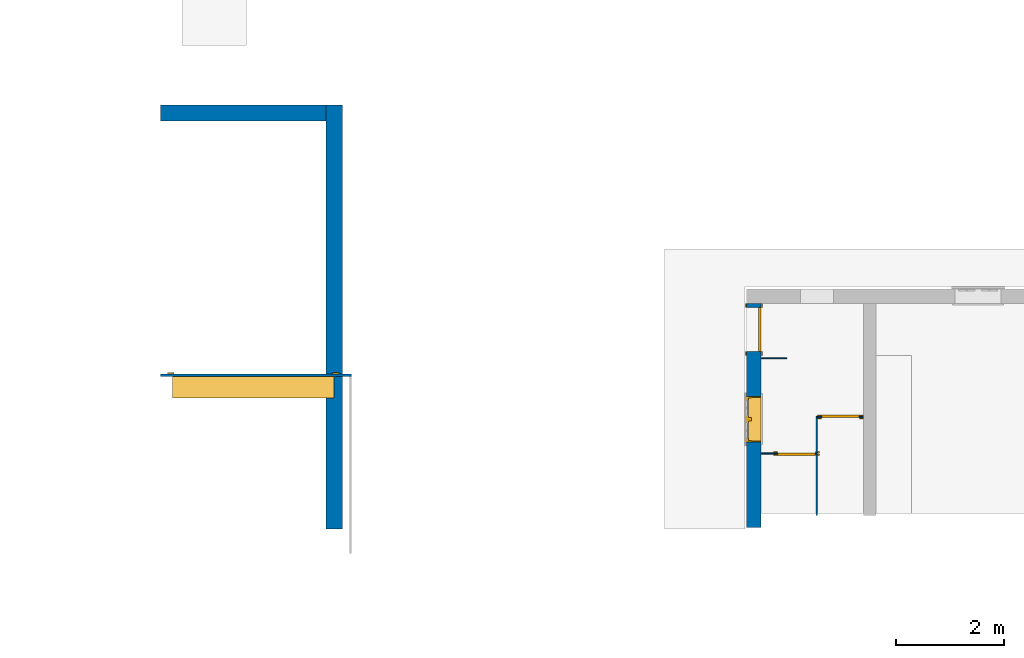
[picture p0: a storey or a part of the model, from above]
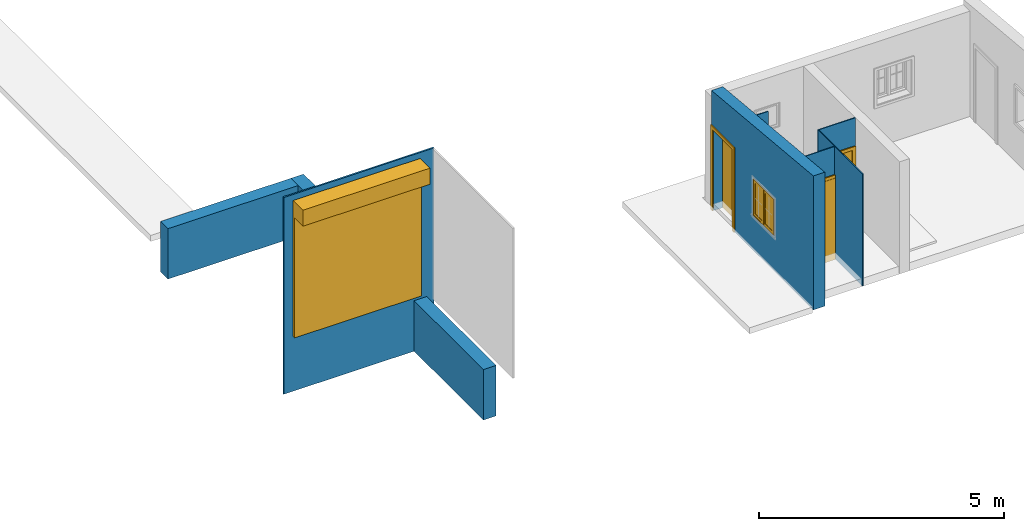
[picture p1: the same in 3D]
Properties of the parts of a building model (IFC2X3)

# File
Description: ViewDefinition [CoordinationView_V2.0]
File name: 1439
Time: 2020-03-18T17:45:13
Written by: The EXPRESS Data Manager Version 5.02.0100.07 : 28 Aug 2013
Made in: 20181011_1500(x64) - Exporter 18.3.2.7 - Alternate UI 18.3.2.7
Comment: STEP Physical File produced by: The EXPRESS Data Manager Version 5.02.0100.07 : 28 Aug 2013 * Module: EDMstepFileFactory/EDMstandAlone * Creation date: Wed Mar 18 17:45:13 2020 * Host: USER-PC * Database: C:\Users\xolad\AppData\Local\Temp\{D7F0864C-7578-4FBB-A1C1-AD8B3B978229}\ifc * Database version: 5507 * Database creation date: Wed Mar 18 17:45:00 2020 * Schema: IFC2X3 * Model: DataRepository.ifc * Model creation date: Wed Mar 18 17:45:00 2020 * Header model: DataRepository.ifc_HeaderModel * Header model creation date: Wed Mar 18 17:45:00 2020 * EDMuser: sdai-user * EDMgroup: sdai-group * License ID and type: 5605 : Permanent license. Expiry date: * EDMstepFileFactory options: 020000

# IfcProject, 1439
LongName: Sundale expansion; Phase: Concept

# IfcSite, Surface:366804
RefLatitude: 42, 24, 53, 508911; RefLongitude: -71, -15, -29, -58837; RefElevation: -44170 mm

# IfcBuilding
Pset_BuildingCommon - NumberOfStoreys: 7

# IfcBuildingStorey (7)
Name | LongName | Elevation (mm)
0. Base level | 0. Base level | 0
Hardstand | Hardstand | 42810
Ground FFL | Ground FFL | 44170
Ceiling 3500 | Ceiling 3500 | 47670
First floor | First floor | 48170
Ceiling 6000 | Ceiling 6000 | 50170
2nd floor | 2nd floor | 51027.1

# IfcBuildingElementProxy: Fascia:Fascia (2)
In: Ground FFL
Pset_BuildingElementProxyCommon - Reference: Fascia
Name (Fascia:...)
Fascia | Group: Model Group:Group 6:617275
Fascia

# IfcBuildingElementProxy: Generic Models 1, Generic Models 17:Generic Models 1:362068
In: Ground FFL
Pset_BuildingElementProxyCommon - Reference: Generic Models 1

# IfcBuildingElementProxy: Generic Models 12 (2)
In: 2nd floor
Pset_BuildingElementProxyCommon - Reference: Generic Models 12
Name
Generic Models 27:Generic Models 12:363948
Generic Models 28:Generic Models 12:363960

# IfcBuildingElementProxy: Generic Models 16, Generic Models 16:Generic Models 16:437957
In: First floor
Type - Material: Column
Pset_BuildingElementProxyCommon - Reference: Generic Models 16

# IfcBuildingElementProxy: Generic Models 2 (2)
In: 2nd floor
Type - Material: Orange
Pset_BuildingElementProxyCommon - Reference: Generic Models 2
Name
Generic Models 18:Generic Models 2:362203
Generic Models 19:Generic Models 2:362217

# IfcBuildingElementProxy: Generic Models 23 (2)
Type - Material: Aluminum, Anodized Silver
Pset_BuildingElementProxyCommon - Reference: Generic Models 23
Name | In
Generic Models 23:Generic Models 23:452494 | Ceiling 3500
Generic Models 26:Generic Models 23:457799 | Ceiling 6000

# IfcBuildingElementProxy: Generic Models 24, Generic Models 24:Generic Models 24:468942
In: First floor
Pset_BuildingElementProxyCommon - Reference: Generic Models 24

# IfcBuildingElementProxy: Generic Models 30, Generic Models 30:Generic Models 30:745945
In: Hardstand
Type - Material: Aluminum, Anodized Silver
Pset_BuildingElementProxyCommon - Reference: Generic Models 30

# IfcBuildingElementProxy: Generic Models 32, Generic Models 64:Generic Models 32:691842
In: Ground FFL
Type - Material: Parking Stripe
Pset_BuildingElementProxyCommon - Reference: Generic Models 32
Group: Model Group:Group 8:726659

# IfcBuildingElementProxy: Generic Models 32 (10)
In: Ground FFL
Type - Material: conc bund
Pset_BuildingElementProxyCommon - Reference: Generic Models 32
Group: Model Group:Group 8:726659
Name
Generic Models 32:Generic Models 32:688641
Generic Models 34:Generic Models 32:688682
Generic Models 61:Generic Models 32:688970
Generic Models 65:Generic Models 32:689397
Generic Models 66:Generic Models 32:689933
Generic Models 38:Generic Models 32:690142
Generic Models 62:Generic Models 32:690381
Generic Models 40:Generic Models 32:691201
Generic Models 67:Generic Models 32:726229
Generic Models 63:Generic Models 32:770716

# IfcBuildingElementProxy: Generic Models 4, Generic Models 20:Generic Models 4:362298
In: Hardstand
Type - Material: Copper
Pset_BuildingElementProxyCommon - Reference: Generic Models 4

# IfcBuildingElementProxy: Generic Models 43, Generic Models 43:Generic Models 43:692555
In: 2nd floor
Type - Material: Aluminum, Anodized Silver
Pset_BuildingElementProxyCommon - Reference: Generic Models 43

# IfcBuildingElementProxy: Generic Models 44 (17)
Type - Material: bollards
Pset_BuildingElementProxyCommon - Reference: Generic Models 44
Name | In | Group
Generic Models 44:Generic Models 44:753895 | 0. Base level
Generic Models 45:Generic Models 44:754462 | 0. Base level | Model Group:Array Group 3:754972
Generic Models 46:Generic Models 44:754982 | 0. Base level | Model Group:Array Group 3:754991
Generic Models 47:Generic Models 44:755017 | 0. Base level | Model Group:Array Group 3:755026
Generic Models 48:Generic Models 44:755035 | 0. Base level | Model Group:Array Group 3:755044
Generic Models 49:Generic Models 44:755053 | 0. Base level | Model Group:Array Group 3:755062
Generic Models 50:Generic Models 44:755071 | 0. Base level | Model Group:Array Group 3:755080
Generic Models 51:Generic Models 44:755089 | 0. Base level | Model Group:Array Group 3:755098
Generic Models 52:Generic Models 44:755107 | 0. Base level | Model Group:Array Group 3:755116
Generic Models 53:Generic Models 44:755125 | 0. Base level | Model Group:Array Group 3:755134
Generic Models 54:Generic Models 44:755143 | 0. Base level | Model Group:Array Group 3:755152
Generic Models 55:Generic Models 44:755161 | 0. Base level | Model Group:Array Group 3:755170
Generic Models 56:Generic Models 44:755179 | 0. Base level | Model Group:Array Group 3:755188
Generic Models 57:Generic Models 44:755197 | 0. Base level | Model Group:Array Group 3:755206
Generic Models 58:Generic Models 44:755215 | 0. Base level | Model Group:Array Group 3:755224
Generic Models 59:Generic Models 44:757700 | 0. Base level
Generic Models 60:Generic Models 44:758977 | Hardstand

# IfcBuildingElementProxy: Generic Models 5 (3)
In: First floor
Type - Material: Column
Pset_BuildingElementProxyCommon - Reference: Generic Models 5
Name
Generic Models 22:Generic Models 5:363155
Generic Models 9:Generic Models 5:470025
Generic Models 29:Generic Models 5:485776

# IfcBuildingElementProxy: Generic Models 68, Generic Models 68:Generic Models 68:786691
In: Ceiling 3500
Type - Material: fence
Pset_BuildingElementProxyCommon - Reference: Generic Models 68

# IfcBuildingElementProxy: Generic Models 7 (3)
Type - Material: Column
Pset_BuildingElementProxyCommon - Reference: Generic Models 7
Name | In
Generic Models 21:Generic Models 7:362919 | 0. Base level
Generic Models 7:Generic Models 7:430327 | Ground FFL
Generic Models 15:Generic Models 7:435619 | Ground FFL

# IfcBuildingElementProxy: Japanese Maple - 3.0 Meters (3)
In: Hardstand
Pset_BuildingElementProxyCommon - Reference: Japanese Maple - 3.0 Meters
Name (M_RPC Tree - Deciduous:Japanese Maple - 3.0 Meters:...)
405666
405705
405730

# IfcBuildingElementProxy: Largetooth Aspen - 7.6 Meters (2)
Pset_BuildingElementProxyCommon - Reference: Largetooth Aspen - 7.6 Meters
Name (M_RPC Tree - Deciduous:Largetooth Aspen - 7.6 Meters:...) | In
465073 | 0. Base level
465143 | Hardstand

# IfcBuildingElementProxy: Lombardy Poplar - 12.2 Meters (2)
In: Hardstand
Pset_BuildingElementProxyCommon - Reference: Lombardy Poplar - 12.2 Meters
Name (M_RPC Tree - Deciduous:Lombardy Poplar - 12.2 Meters:...)
465183
465230

# IfcBuildingElementProxy: M_Muntin Pattern_2x2 (6)
In: Hardstand
Type - Material: Clad - White, Wood - Stained
Pset_BuildingElementProxyCommon - Reference: M_Muntin Pattern_2x2
Group: Model Group:Group 6:617275
Name (M_Muntin Pattern_2x2:M_Muntin Pattern_2x2:...)
534044
534045
536291
536292
536326
536327

# IfcBuildingElementProxy: Picture Frame (3)
In: Hardstand
Type - Material: Wood - Stained
Pset_BuildingElementProxyCommon - Reference: Picture Frame
Group: Model Group:Group 6:617275
Name (M_Trim-Window-Interior-Flat:Picture Frame:...)
534047
536294
536329

# IfcBuildingElementProxy: Truck03 (3)
Pset_BuildingElementProxyCommon - Reference: Truck03
Name (Truck03:Truck03:...) | In
362314 | Ground FFL
363380 | Hardstand
363381 | Hardstand

# IfcBuildingElementProxy: locker (7)
In: 2nd floor
Type - Material: Laminate, Ivory, Matte, Wood Sheathing, Chipboard
Pset_BuildingElementProxyCommon - Reference: locker
Name (locker:locker:...)
509001
510158
510176
510204
510205
510206
511701

# IfcBuildingElementProxy: lockers 2 (47)
In: First floor
Type - Material: Laminate, Ivory, Matte
Pset_BuildingElementProxyCommon - Reference: lockers 2
Name (lockers 2:lockers 2:...) | Group
636421 | Model Group:Array Group 1:636530
636635 | Model Group:Array Group 1:636636
636703 | Model Group:Array Group 1:636704
636735 | Model Group:Array Group 1:636736
636767 | Model Group:Array Group 1:636768
636799 | Model Group:Array Group 1:636800
636831 | Model Group:Array Group 1:636832
636863 | Model Group:Array Group 1:636864
636895 | Model Group:Array Group 1:636896
636927 | Model Group:Array Group 1:636928
636959 | Model Group:Array Group 1:636960
636991 | Model Group:Array Group 1:636992
637023 | Model Group:Array Group 1:637024
637055 | Model Group:Array Group 1:637056
637087 | Model Group:Array Group 1:637088
637119 | Model Group:Array Group 1:637120
637162 | Model Group:Array Group 1:637163
637194 | Model Group:Array Group 1:637195
637268 | Model Group:Array Group 1:637269
637300 | Model Group:Array Group 1:637301
637348 | Model Group:Array Group 1:637349
637380 | Model Group:Array Group 1:637381
637456 | Model Group:Array Group 1:637457
637488 | Model Group:Array Group 1:637489
637520 | Model Group:Array Group 1:637521
637552 | Model Group:Array Group 1:637553
637584 | Model Group:Array Group 1:637585
637616 | Model Group:Array Group 1:637617
637648 | Model Group:Array Group 1:637649
637680 | Model Group:Array Group 1:637681
637712 | Model Group:Array Group 1:637713
637755 | Model Group:Array Group 1:637756
637815 | Model Group:Array Group 1:637816
637874 | Model Group:Array Group 1:637875
637939 | Model Group:Array Group 1:637940
638002 | Model Group:Array Group 1:638003
638034 | Model Group:Array Group 1:638035
638066 | Model Group:Array Group 1:638067
638098 | Model Group:Array Group 1:638099
638142 | Model Group:Array Group 1:638143
638184 | Model Group:Array Group 1:638185
638186 | Model Group:Array Group 1:638187
638188 | Model Group:Array Group 1:638189
638190 | Model Group:Array Group 1:638191
638192 | Model Group:Array Group 1:638193
638194 | Model Group:Array Group 1:638195
638196 | Model Group:Array Group 1:638197

# IfcBuildingElementProxy: turnstile (2)
In: Ground FFL
Type - Material: metal
Pset_BuildingElementProxyCommon - Reference: turnstile
Name (turnstile:turnstile:...)
711251
712248

# IfcBuildingElementProxy: with Sill (3)
In: Hardstand
Type - Material: Clad - White
Pset_BuildingElementProxyCommon - Reference: with Sill
Group: Model Group:Group 6:617275
Name (M_Trim-Window-Exterior-Flat:with Sill:...)
534046
536293
536328

# IfcCurtainWall: Curtain Wall:Storefront (14)
Pset_CurtainWallCommon - IsExternal: yes; Reference: Storefront
Name (Curtain Wall:Storefront:...) | In
363622 | Ground FFL
452065 | Ground FFL
573182 | 2nd floor
590973 | Ground FFL
624712 | Ground FFL
624715 | Ground FFL
624717 | Ground FFL
624719 | Ground FFL
652019 | First floor
652436 | First floor
662282 | 2nd floor
662335 | 2nd floor
679730 | Ground FFL
679854 | Ground FFL

# IfcDoor: 0813 x 2030mm (4)
Type - OperationType: SINGLE_SWING_LEFT; ParameterTakesPrecedence: no; Sizeable: no; Material: Door - Frame, Door - Panel
Type - M_Single-Flush:0813 x 2030mm:511926 - PanelOperation: SWINGING
OverallHeight: 2030 mm; OverallWidth: 813 mm
Pset_DoorCommon - IsExternal: no; Reference: 0813 x 2030mm; ThermalTransmittance: 3.7021 kg/K/s3
Name (M_Single-Flush:0813 x 2030mm:...) | In
511926 | 2nd floor
524189 | First floor
525468 | First floor
580034 | First floor

# IfcDoor: 0813 x 2030mm, M_Single-Flush:0813 x 2030mm:520814
In: First floor
Type - OperationType: SINGLE_SWING_LEFT; ParameterTakesPrecedence: no; Sizeable: no; Material: Door - Frame, Door - Panel
Type - M_Single-Flush:0813 x 2030mm:520814 - PanelOperation: SWINGING
OverallHeight: 2030 mm; OverallWidth: 813 mm
Pset_DoorCommon - IsExternal: no; Reference: 0813 x 2030mm; ThermalTransmittance: 3.7021 kg/K/s3

# IfcDoor: 0813 x 2030mm (3)
In: First floor
Type - OperationType: SINGLE_SWING_LEFT; ParameterTakesPrecedence: no; Sizeable: no; Material: Door - Frame, Door - Panel
Type - M_Single-Flush:0813 x 2030mm:525263 - PanelOperation: SWINGING
OverallHeight: 2030 mm; OverallWidth: 813 mm
Pset_DoorCommon - IsExternal: no; Reference: 0813 x 2030mm; ThermalTransmittance: 3.7021 kg/K/s3
Name (M_Single-Flush:0813 x 2030mm:...)
525263
525330
579933

# IfcDoor: 0813 x 2030mm, M_Single-Flush:0813 x 2030mm:535025
In: Hardstand
Type - OperationType: SINGLE_SWING_LEFT; ParameterTakesPrecedence: no; Sizeable: no; Material: Door - Frame, Door - Panel
Type - M_Single-Flush:0813 x 2030mm:535025 - PanelOperation: SWINGING
OverallHeight: 2030 mm; OverallWidth: 813 mm; Group: Model Group:Group 6:617275
Pset_DoorCommon - IsExternal: no; Reference: 0813 x 2030mm; ThermalTransmittance: 3.7021 kg/K/s3

# IfcDoor: 0813 x 2030mm (4)
Type - OperationType: SINGLE_SWING_RIGHT; ParameterTakesPrecedence: no; Sizeable: no; Material: Door - Frame, Door - Panel
Type - M_Single-Flush:0813 x 2030mm:512172 - PanelOperation: SWINGING
OverallHeight: 2030 mm; OverallWidth: 813 mm
Pset_DoorCommon - IsExternal: no; Reference: 0813 x 2030mm; ThermalTransmittance: 3.7021 kg/K/s3
Name (M_Single-Flush:0813 x 2030mm:...) | In
512172 | 2nd floor
523256 | First floor
524791 | First floor
524841 | First floor

# IfcDoor: 0813 x 2030mm, M_Single-Flush:0813 x 2030mm:521029
In: 2nd floor
Type - OperationType: SINGLE_SWING_RIGHT; ParameterTakesPrecedence: no; Sizeable: no; Material: Door - Frame, Door - Panel
Type - M_Single-Flush:0813 x 2030mm:521029 - PanelOperation: SWINGING
OverallHeight: 2030 mm; OverallWidth: 813 mm
Pset_DoorCommon - IsExternal: no; Reference: 0813 x 2030mm; ThermalTransmittance: 3.7021 kg/K/s3

# IfcDoor: 0813 x 2030mm (2)
Type - OperationType: SINGLE_SWING_RIGHT; ParameterTakesPrecedence: no; Sizeable: no; Material: Door - Frame, Door - Panel
Type - M_Single-Flush:0813 x 2030mm:522150 - PanelOperation: SWINGING
OverallHeight: 2030 mm; OverallWidth: 813 mm
Pset_DoorCommon - IsExternal: no; Reference: 0813 x 2030mm; ThermalTransmittance: 3.7021 kg/K/s3
Name (M_Single-Flush:0813 x 2030mm:...) | In
522150 | 2nd floor
536511 | Ground FFL

# IfcDoor: 0813 x 2030mm (4)
In: First floor
Type - OperationType: SINGLE_SWING_RIGHT; ParameterTakesPrecedence: no; Sizeable: no; Material: Door - Frame, Door - Panel
Type - M_Single-Flush:0813 x 2030mm:527921 - PanelOperation: SWINGING
OverallHeight: 2030 mm; OverallWidth: 813 mm
Pset_DoorCommon - IsExternal: no; Reference: 0813 x 2030mm; ThermalTransmittance: 3.7021 kg/K/s3
Name (M_Single-Flush:0813 x 2030mm:...)
527921
528006
528034
528060

# IfcDoor: 0813 x 2030mm, M_Single-Flush:0813 x 2030mm:534794
In: Hardstand
Type - OperationType: SINGLE_SWING_RIGHT; ParameterTakesPrecedence: no; Sizeable: no; Material: Door - Frame, Door - Panel
Type - M_Single-Flush:0813 x 2030mm:534794 - PanelOperation: SWINGING
OverallHeight: 2030 mm; OverallWidth: 813 mm; Group: Model Group:Group 6:617275
Pset_DoorCommon - IsExternal: no; Reference: 0813 x 2030mm; ThermalTransmittance: 3.7021 kg/K/s3

# IfcDoor: 0813 x 2134mm, M_Single-Flush:0813 x 2134mm:640715
In: First floor
Type - OperationType: SINGLE_SWING_LEFT; ParameterTakesPrecedence: no; Sizeable: no; Material: Door - Frame, Door - Panel
Type - M_Single-Flush:0813 x 2134mm:640715 - PanelOperation: SWINGING
OverallHeight: 2134 mm; OverallWidth: 813 mm
Pset_DoorCommon - IsExternal: no; Reference: 0813 x 2134mm; ThermalTransmittance: 3.7021 kg/K/s3

# IfcDoor: 1050 x 2134mm (7)
In: Ground FFL
Type - OperationType: SINGLE_SWING_LEFT; ParameterTakesPrecedence: no; Sizeable: no; Material: Door - Frame, Door - Panel
Type - M_Single-Flush:1050 x 2134mm:525980 - PanelOperation: SWINGING
OverallHeight: 2134 mm; OverallWidth: 1050 mm
Pset_DoorCommon - IsExternal: no; Reference: 1050 x 2134mm; ThermalTransmittance: 3.7021 kg/K/s3
Name (M_Single-Flush:1050 x 2134mm:...)
525980
526156
526285
526328
526460
659010
782430

# IfcDoor: 1050 x 2134mm, M_Single-Flush:1050 x 2134mm:769808
In: First floor
Type - OperationType: SINGLE_SWING_LEFT; ParameterTakesPrecedence: no; Sizeable: no; Material: Door - Frame, Door - Panel
Type - M_Single-Flush:1050 x 2134mm:769808 - PanelOperation: SWINGING
OverallHeight: 2134 mm; OverallWidth: 1050 mm
Pset_DoorCommon - IsExternal: no; Reference: 1050 x 2134mm; ThermalTransmittance: 3.7021 kg/K/s3

# IfcDoor: 1050 x 2134mm (8)
In: Ground FFL
Type - OperationType: SINGLE_SWING_RIGHT; ParameterTakesPrecedence: no; Sizeable: no; Material: Door - Frame, Door - Panel
Type - M_Single-Flush:1050 x 2134mm:526187 - PanelOperation: SWINGING
OverallHeight: 2134 mm; OverallWidth: 1050 mm
Pset_DoorCommon - IsExternal: no; Reference: 1050 x 2134mm; ThermalTransmittance: 3.7021 kg/K/s3
Name (M_Single-Flush:1050 x 2134mm:...)
526187
526288
526434
659299
659471
660703
660745
678601

# IfcDoor: 1050 x 3000mm, M_Single-Flush:1050 x 3000mm:526374
In: Ground FFL
Type - OperationType: SINGLE_SWING_LEFT; ParameterTakesPrecedence: no; Sizeable: no; Material: Door - Frame, Door - Panel
Type - M_Single-Flush:1050 x 3000mm:526374 - PanelOperation: SWINGING
OverallHeight: 3000 mm; OverallWidth: 1050 mm
Pset_DoorCommon - IsExternal: no; Reference: 1050 x 3000mm; ThermalTransmittance: 3.7021 kg/K/s3

# IfcDoor: 1050 x 3000mm, M_Single-Flush:1050 x 3000mm:526406
In: Ground FFL
Type - OperationType: SINGLE_SWING_RIGHT; ParameterTakesPrecedence: no; Sizeable: no; Material: Door - Frame, Door - Panel
Type - M_Single-Flush:1050 x 3000mm:526406 - PanelOperation: SWINGING
OverallHeight: 3000 mm; OverallWidth: 1050 mm
Pset_DoorCommon - IsExternal: no; Reference: 1050 x 3000mm; ThermalTransmittance: 3.7021 kg/K/s3

# IfcDoor: 25000(w) x 3000(h) (6)
In: Ground FFL
Type - ParameterTakesPrecedence: no; Sizeable: no; Material: Metal - Paint Finish - Ivory, Matte, Metal - Galvanised
OverallHeight: 3000 mm; OverallWidth: 2500 mm
Pset_DoorCommon - IsExternal: yes; Reference: 25000(w) x 3000(h)
Name (Rollershutter:25000(w) x 3000(h):...)
363164
678529
678631
678650
781874
782168

# IfcDoor: 3000(w) x 3000(h) (3)
In: Ground FFL
Type - ParameterTakesPrecedence: no; Sizeable: no; Material: Metal - Paint Finish - Ivory, Matte, Metal - Galvanised
OverallHeight: 3000 mm; OverallWidth: 3000 mm
Pset_DoorCommon - IsExternal: yes; Reference: 3000(w) x 3000(h)
Name (Rollershutter:3000(w) x 3000(h):...)
440970
441001
681902

# IfcDoor: 3000(w) x 3000(h) (15)
In: Ground FFL
Type - ParameterTakesPrecedence: no; Sizeable: no; Material: Metal - Steel - Richards Wilcox - Painted - Brown - Ribbed, Metal - Steel - Richards Wilcox - Galvanized, Glazing - Richards Wilcox - Clear, Metal - Steel - Richards Wilcox - Painted - Black, Analytical Floor Surface, Rubber - Richards Wilcox - Black
OverallHeight: 3000 mm; OverallWidth: 2200 mm
Pset_DoorCommon - IsExternal: yes; Reference: 3000(w) x 3000(h)
Name (6m_Roller Shutter Doors:3000(w) x 3000(h):...)
399966
412640
412870
412898
412903
412908
412913
412918
412923
412928
412933
412938
412943
412948
412953

# IfcDoor: 700 x 2030mm (2)
In: 2nd floor
Type - OperationType: SINGLE_SWING_LEFT; ParameterTakesPrecedence: no; Sizeable: no; Material: Door - Frame, Door - Panel
Type - M_Single-Flush:700 x 2030mm:511005 - PanelOperation: SWINGING
OverallHeight: 2030 mm; OverallWidth: 700 mm
Pset_DoorCommon - IsExternal: no; Reference: 700 x 2030mm; ThermalTransmittance: 3.7021 kg/K/s3
Name (M_Single-Flush:700 x 2030mm:...)
511005
511007

# IfcDoor: 700 x 2030mm, M_Single-Flush:700 x 2030mm:572632
In: 2nd floor
Type - OperationType: SINGLE_SWING_LEFT; ParameterTakesPrecedence: no; Sizeable: no; Material: Door - Frame, Door - Panel
Type - M_Single-Flush:700 x 2030mm:572632 - PanelOperation: SWINGING
OverallHeight: 2030 mm; OverallWidth: 700 mm
Pset_DoorCommon - IsExternal: no; Reference: 700 x 2030mm; ThermalTransmittance: 3.7021 kg/K/s3

# IfcDoor: 700 x 2030mm (4)
Type - OperationType: SINGLE_SWING_RIGHT; ParameterTakesPrecedence: no; Sizeable: no; Material: Door - Frame, Door - Panel
Type - M_Single-Flush:700 x 2030mm:511009 - PanelOperation: SWINGING
OverallHeight: 2030 mm; OverallWidth: 700 mm
Pset_DoorCommon - IsExternal: no; Reference: 700 x 2030mm; ThermalTransmittance: 3.7021 kg/K/s3
Name (M_Single-Flush:700 x 2030mm:...) | In
511009 | 2nd floor
511010 | 2nd floor
533854 | Hardstand | Group: Model Group:Group 6:617275
533856 | Hardstand | Group: Model Group:Group 6:617275

# IfcDoor: 700 x 2030mm (2)
In: First floor
Type - OperationType: SINGLE_SWING_RIGHT; ParameterTakesPrecedence: no; Sizeable: no; Material: Door - Frame, Door - Panel
Type - M_Single-Flush:700 x 2030mm:524607 - PanelOperation: SWINGING
OverallHeight: 2030 mm; OverallWidth: 700 mm
Pset_DoorCommon - IsExternal: no; Reference: 700 x 2030mm; ThermalTransmittance: 3.7021 kg/K/s3
Name (M_Single-Flush:700 x 2030mm:...)
524607
524656

# IfcDoor: 700 x 2030mm, M_Single-Flush:700 x 2030mm:553800
In: Hardstand
Type - OperationType: SINGLE_SWING_RIGHT; ParameterTakesPrecedence: no; Sizeable: no; Material: Door - Frame, Door - Panel
Type - M_Single-Flush:700 x 2030mm:553800 - PanelOperation: SWINGING
OverallHeight: 2030 mm; OverallWidth: 700 mm
Pset_DoorCommon - IsExternal: no; Reference: 700 x 2030mm; ThermalTransmittance: 3.7021 kg/K/s3

# IfcDoor: 700 x 2030mm, M_Single-Flush:700 x 2030mm:588641
In: Hardstand
Type - OperationType: SINGLE_SWING_RIGHT; ParameterTakesPrecedence: no; Sizeable: no; Material: Door - Frame, Door - Panel
Type - M_Single-Flush:700 x 2030mm:588641 - PanelOperation: SWINGING
OverallHeight: 2030 mm; OverallWidth: 700 mm
Pset_DoorCommon - IsExternal: no; Reference: 700 x 2030mm; ThermalTransmittance: 3.7021 kg/K/s3

# IfcDoor: 813 x 2030mm (2)
In: First floor
Type - OperationType: SINGLE_SWING_LEFT; ParameterTakesPrecedence: no; Sizeable: no; Material: Door - Frame, Door - Panel
Type - M_Single-Flush:813 x 2030mm:406399 - PanelOperation: SWINGING
OverallHeight: 2030 mm; OverallWidth: 813 mm
Pset_DoorCommon - IsExternal: no; Reference: 813 x 2030mm; ThermalTransmittance: 3.7021 kg/K/s3
Name (M_Single-Flush:813 x 2030mm:...)
406399
621226

# IfcDoor: 813 x 2030mm, M_Single-Flush:813 x 2030mm:457723
In: Ground FFL
Type - OperationType: SINGLE_SWING_RIGHT; ParameterTakesPrecedence: no; Sizeable: no; Material: Door - Frame, Door - Panel
Type - M_Single-Flush:813 x 2030mm:457723 - PanelOperation: SWINGING
OverallHeight: 2030 mm; OverallWidth: 813 mm
Pset_DoorCommon - IsExternal: no; Reference: 813 x 2030mm; ThermalTransmittance: 3.7021 kg/K/s3

# IfcDoor: 813 x 2030mm (2)
In: First floor
Type - OperationType: SINGLE_SWING_RIGHT; ParameterTakesPrecedence: no; Sizeable: no; Material: Door - Frame, Door - Panel
Type - M_Single-Flush:813 x 2030mm:493220 - PanelOperation: SWINGING
OverallHeight: 2030 mm; OverallWidth: 813 mm
Pset_DoorCommon - IsExternal: no; Reference: 813 x 2030mm; ThermalTransmittance: 3.7021 kg/K/s3
Name (M_Single-Flush:813 x 2030mm:...)
493220
641769

# IfcDoor: 813 x 2030mm, M_Single-Flush:813 x 2030mm:784138
In: First floor
Type - OperationType: SINGLE_SWING_RIGHT; ParameterTakesPrecedence: no; Sizeable: no; Material: Door - Frame, Door - Panel
Type - M_Single-Flush:813 x 2030mm:784138 - PanelOperation: SWINGING
OverallHeight: 2030 mm; OverallWidth: 813 mm
Pset_DoorCommon - IsExternal: no; Reference: 813 x 2030mm; ThermalTransmittance: 3.7021 kg/K/s3

# IfcFlowTerminal: Concorde 510 (14)
Classification: D2010440 Sinks - Service (Uniformat)
Pset_ManufacturerTypeInformation - Manufacturer: VAAL
Pset_DistributionFlowElementCommon - Reference: Concorde 510
Name (duravit automatic tap no pedestal:Concorde 510:...) | In
501603 | 2nd floor
510610 | 2nd floor
510645 | 2nd floor
528683 | First floor
528718 | First floor
528761 | First floor
528808 | First floor
528867 | First floor
528896 | First floor
528927 | First floor
528954 | First floor
529224 | First floor
529317 | First floor
533354 | Ground FFL | Group: Model Group:Group 6:617275

# IfcFlowTerminal: Lavatera (8)
Classification: D2010210 Urinals - Single (Uniformat); Material: Porcelain - Linen
Pset_ManufacturerTypeInformation - Manufacturer: VAAL
Pset_DistributionFlowElementCommon - Reference: Lavatera
Name (Lavatera with Cobra Sensor:Lavatera:...) | In
511117 | 2nd floor
511118 | 2nd floor
511119 | 2nd floor
527367 | First floor
527396 | First floor
527447 | First floor
527478 | First floor
533690 | Ground FFL | Group: Model Group:Group 6:617275

# IfcFurnishingElement: Desk 900x1800 (7)
Type - ElementType: Desk 900x1800; Material: Paint - White
Name (Desk 900x1800:Desk 900x1800:...) | In
522024 | 2nd floor
522053 | 2nd floor
522074 | 2nd floor
522079 | 2nd floor
522100 | 2nd floor
522105 | 2nd floor
535153 | Ground FFL | Group: Model Group:Group 6:617275

# IfcFurnishingElement: Desk Chair (30)
Type - ElementType: Desk Chair; Material: Metal - Chrome, Textile - Slate Blue
Name (M_Chair-Desk:Desk Chair:...) | In
522025 | 2nd floor
522026 | 2nd floor
522027 | 2nd floor
522028 | 2nd floor
522054 | 2nd floor
522055 | 2nd floor
522056 | 2nd floor
522057 | 2nd floor
522075 | 2nd floor
522076 | 2nd floor
522077 | 2nd floor
522078 | 2nd floor
522080 | 2nd floor
522081 | 2nd floor
522082 | 2nd floor
522083 | 2nd floor
522101 | 2nd floor
522102 | 2nd floor
522103 | 2nd floor
522104 | 2nd floor
522106 | 2nd floor
522107 | 2nd floor
522108 | 2nd floor
522109 | 2nd floor
535154 | Ground FFL | Group: Model Group:Group 6:617275
535155 | Ground FFL | Group: Model Group:Group 6:617275
535156 | Ground FFL | Group: Model Group:Group 6:617275
535157 | Ground FFL | Group: Model Group:Group 6:617275
535215 | Ground FFL | Group: Model Group:Group 6:617275
535262 | Ground FFL | Group: Model Group:Group 6:617275

# IfcMember: Curtain Wall:Storefront:8486 (147)
Material: Aluminium
Pset_MemberCommon - IsExternal: yes; LoadBearing: yes; Reference: 50 x 150mm
Name (Curtain Wall:Storefront:...) | In | Span (mm)
4 x 8486 | Ground FFL | 875
3 x 8486 | Ground FFL | 920
6 x 8486 | Ground FFL | 1429.82
5 x 8486 | Ground FFL | 2220
5 x 8486 | Ground FFL | 580
6 x 8486 | Ground FFL | 1454.82
4 x 8486 | 2nd floor | 1425
4 x 8486 | 2nd floor | 966.879
2 x 8486 | 2nd floor | 1450
2 x 8486 | Ground FFL | 900
2 x 8486 | Ground FFL | 1000
12 x 8486 | Ground FFL | 991.667
20 x 8486 | Ground FFL | 2400
8 x 8486 | Ground FFL | 601.146
6 x 8486 | Ground FFL | 1016.67
12 x 8486 | Ground FFL | 941.667
6 x 8486 | Ground FFL | 966.667
14 x 8486 | Ground FFL | 600
4 x 8486 | First floor | 735
3 x 8486 | First floor | 900
4 x 8486 | First floor | 775
3 x 8486 | First floor | 770.489
4 x 8486 | 2nd floor | 1300
4 x 8486 | 2nd floor | 908.331
4 x 8486 | Ground FFL | 1600

# IfcMember: Stringer:Stringer - 50mm Width (71)
Type - PredefinedType: STRINGER
Pset_MemberCommon - IsExternal: no; LoadBearing: yes
Name (Assembled Stair:Stair:...) | In | Reference | Span (mm) | Slope (deg)
371358 Stringer 1 | Ground FFL | 170mm max riser 270mm going | 50 | 0
371358 Stringer 2 | Ground FFL | 170mm max riser 270mm going | 50 | 0
516542 Stringer 1 | Ground FFL | 190mm max riser 250mm going | 50 | 0
516542 Stringer 2 | Ground FFL | 190mm max riser 250mm going | 50 | 0
516542 Stringer 3 | Ground FFL | 190mm max riser 250mm going | 50 | 0
516542 Stringer 4 | Ground FFL | 190mm max riser 250mm going | 50 | 0
516542 Stringer 5 | Ground FFL | 190mm max riser 250mm going | 50 | 0
516542 Stringer 6 | Ground FFL | 190mm max riser 250mm going | 50 | 0
516542 Stringer 7 | Ground FFL | 190mm max riser 250mm going | 50 | 0
516542 Stringer 8 | Ground FFL | 190mm max riser 250mm going | 50 | 0
516542 Stringer 9 | Ground FFL | 190mm max riser 250mm going | 50 | 0
516542 Stringer 10 | Ground FFL | 190mm max riser 250mm going | 50 | 0
516542 Stringer 11 | Ground FFL | 190mm max riser 250mm going | 50 | 0
516542 Stringer 12 | Ground FFL | 190mm max riser 250mm going | 50 | 0
516542 Stringer 13 | Ground FFL | 190mm max riser 250mm going | 50 | 0
516542 Stringer 14 | Ground FFL | 190mm max riser 250mm going | 50 | 0
588793 Stringer 1 | Ground FFL | 170mm max riser 270mm going | 50 | 0
588793 Stringer 2 | Ground FFL | 170mm max riser 270mm going | 50 | 0
621048 Stringer 1 | Ground FFL | 170mm max riser 270mm going | 50 | 0
621048 Stringer 2 | Ground FFL | 170mm max riser 270mm going | 50 | 0
621048 Stringer 3 | Ground FFL | 170mm max riser 270mm going | 50 | 0
621048 Stringer 4 | Ground FFL | 170mm max riser 270mm going | 50 | 0
621048 Stringer 5 | Ground FFL | 170mm max riser 270mm going | 50 | 0
621048 Stringer 6 | Ground FFL | 170mm max riser 270mm going | 50 | 0
621048 Stringer 7 | Ground FFL | 170mm max riser 270mm going | 50 | 0
621048 Stringer 8 | Ground FFL | 170mm max riser 270mm going | 50 | 0
621048 Stringer 9 | Ground FFL | 170mm max riser 270mm going | 50 | 0
621048 Stringer 10 | Ground FFL | 170mm max riser 270mm going | 50 | 0
622611 Stringer 1 | Hardstand | 170mm max riser 270mm going | 50 | 0
622611 Stringer 2 | Hardstand | 170mm max riser 270mm going | 50 | 0
622611 Stringer 3 | Hardstand | 170mm max riser 270mm going | 50 | 0
622611 Stringer 4 | Hardstand | 170mm max riser 270mm going | 50 | 0
622611 Stringer 5 | Hardstand | 170mm max riser 270mm going | 50 | 0
622611 Stringer 6 | Hardstand | 170mm max riser 270mm going | 50 | 0
622611 Stringer 7 | Hardstand | 170mm max riser 270mm going | 50 | 0
622611 Stringer 8 | Hardstand | 170mm max riser 270mm going | 50 | 0
622611 Stringer 9 | Hardstand | 170mm max riser 270mm going | 50 | 0
622611 Stringer 10 | Hardstand | 170mm max riser 270mm going | 50 | 0
622611 Stringer 11 | Hardstand | 170mm max riser 270mm going | 50 | 0
622611 Stringer 12 | Hardstand | 170mm max riser 270mm going | 50 | 0
622611 Stringer 13 | Hardstand | 170mm max riser 270mm going | 50 | 0
622611 Stringer 14 | Hardstand | 170mm max riser 270mm going | 50 | 0
634342 Stringer 1 | First floor | 170mm max riser 270mm going 1500 | 50 | 0
634342 Stringer 2 | First floor | 170mm max riser 270mm going 1500 | 50 | 0
634342 Stringer 3 | First floor | 170mm max riser 270mm going 1500 | 50 | 0
634342 Stringer 4 | First floor | 170mm max riser 270mm going 1500 | 50 | 0
634342 Stringer 5 | First floor | 170mm max riser 270mm going 1500
634342 Stringer 6 | First floor | 170mm max riser 270mm going 1500 | 400 | 0
634342 Stringer 7 | First floor | 170mm max riser 270mm going 1500
634342 Stringer 8 | First floor | 170mm max riser 270mm going 1500 | 400 | 0
712789 Stringer 1 | Hardstand | 170mm max riser 270mm going | 50 | 0
712789 Stringer 2 | Hardstand | 170mm max riser 270mm going | 50 | 0
767068 Stringer 1 | Hardstand | 170mm max riser 270mm going | 50 | 0
767068 Stringer 2 | Hardstand | 170mm max riser 270mm going | 50 | 0
767068 Stringer 3 | Hardstand | 170mm max riser 270mm going | 50 | 0
767068 Stringer 4 | Hardstand | 170mm max riser 270mm going | 50 | 0
767068 Stringer 5 | Hardstand | 170mm max riser 270mm going
767068 Stringer 6 | Hardstand | 170mm max riser 270mm going | 400 | 0
767068 Stringer 7 | Hardstand | 170mm max riser 270mm going
767068 Stringer 8 | Hardstand | 170mm max riser 270mm going | 50 | 0
767068 Stringer 9 | Hardstand | 170mm max riser 270mm going | 50 | 0
767068 Stringer 10 | Hardstand | 170mm max riser 270mm going
767068 Stringer 11 | Hardstand | 170mm max riser 270mm going | 400 | 0
767068 Stringer 12 | Hardstand | 170mm max riser 270mm going
767068 Stringer 13 | Hardstand | 170mm max riser 270mm going
767068 Stringer 14 | Hardstand | 170mm max riser 270mm going | 50 | 0
767068 Stringer 15 | Hardstand | 170mm max riser 270mm going | 50 | 0
767068 Stringer 16 | Hardstand | 170mm max riser 270mm going | 50 | 0
767068 Stringer 17 | Hardstand | 170mm max riser 270mm going | 50 | 0
770226 Stringer 1 | Ceiling 3500 | 170mm max riser 270mm going | 50 | 0
770226 Stringer 2 | Ceiling 3500 | 170mm max riser 270mm going | 50 | 0

# IfcPlate: Glazed (48)
Type - ElementType: Glazed; PredefinedType: CURTAIN_PANEL; Material: Glass
Pset_PlateCommon - IsExternal: yes; Reference: Glazed; LoadBearing: yes; ThermalTransmittance: 6.7069 kg/K/s3
Name (System Panel:Glazed:...) | In
363623 | Ground FFL
570984 | Ground FFL
452066 | Ground FFL
452085 | Ground FFL
452087 | Ground FFL
452089 | Ground FFL
641314 | Ground FFL
641315 | Ground FFL
641316 | Ground FFL
641317 | Ground FFL
573183 | 2nd floor
573568 | 2nd floor
590627 | 2nd floor
590974 | Ground FFL
625227 | Ground FFL
625239 | Ground FFL
625241 | Ground FFL
625243 | Ground FFL
625244 | Ground FFL
625245 | Ground FFL
625228 | Ground FFL
625251 | Ground FFL
625253 | Ground FFL
625255 | Ground FFL
625256 | Ground FFL
625257 | Ground FFL
625229 | Ground FFL
625263 | Ground FFL
625265 | Ground FFL
625267 | Ground FFL
625268 | Ground FFL
625269 | Ground FFL
625230 | Ground FFL
625275 | Ground FFL
625277 | Ground FFL
625279 | Ground FFL
625280 | Ground FFL
625281 | Ground FFL
652020 | First floor
652023 | First floor
652437 | First floor
652439 | First floor
662283 | 2nd floor
662336 | 2nd floor
679731 | Ground FFL
679734 | Ground FFL
679855 | Ground FFL
679858 | Ground FFL

# IfcRailing: Railing:1100mm (21)
Pset_RailingCommon - IsExternal: no; Reference: 1100mm; Height: 1100 mm
Name (Railing:1100mm:...) | In
371363 | Ground FFL
371367 | Ground FFL
529969 | 2nd floor
530150 | 2nd floor
588798 | Ground FFL
588802 | Ground FFL
621073 | Ground FFL
622501 | First floor
633210 | 2nd floor
634572 | First floor
634576 | First floor
635356 | First floor
640224 | First floor
674000 | Ground FFL
712794 | Hardstand
712798 | Hardstand
767745 | Hardstand
767749 | Hardstand
768174 | Ground FFL
770505 | Ceiling 3500
770509 | Ceiling 3500

# IfcRoof: Basic Roof:50 (9)
Pset_RoofCommon - IsExternal: yes; Reference: 50
Name (Basic Roof:50:...) | In | TotalArea (m2) | ProjectedArea (m2)
362139 | Ground FFL | 458.656 | 397.208
362223 | Ground FFL | 394.662 | 393.16
362305 | Ground FFL | 148.952 | 146.689
362950 | Ground FFL | 31.9567 | 31.8351
363126 | Ground FFL | 3866.06 | 3851.35
363387 | Ground FFL | 1768.68 | 1761.95
467344 | Ground FFL | 31.0087 | 30.8907 | Group: Model Group:Group 6:617275
712845 | Ground FFL | 15.0113 | 14.9542
784254 | First floor | 22.8935 | 22.8064

# IfcRoof: Basic Roof:50:346160 (2)
In: Ground FFL
Material: Aluminum
Pset_RoofCommon - IsExternal: yes; Reference: 50
Name (Basic Roof:50:...) | TotalArea (m2) | ProjectedArea (m2)
362014 | 2543.53 | 2369.27
362026 | 2289.14 | 2154.74

# IfcRoof: Basic Roof:Isopanel 100 (2)
Pset_RoofCommon - IsExternal: yes; Reference: Isopanel 100
Name (Basic Roof:Isopanel 100:...) | In | TotalArea (m2) | ProjectedArea (m2)
363962 | Ground FFL | 295.603 | 295.198
515924 | Hardstand | 1346.51 | 1341.39

# IfcSlab: Assembled Stair:170mm max riser 270mm going 1500:768833, Assembled Stair:Stair:634342 Landing 1
In: First floor
PredefinedType: LANDING
Pset_SlabCommon - IsExternal: no; PitchAngle: 0 deg; Reference: Non-Monolithic Landing

# IfcSlab: Assembled Stair:170mm max riser 270mm going:346207 (8)
PredefinedType: LANDING
Pset_SlabCommon - IsExternal: no; PitchAngle: 0 deg; Reference: Non-Monolithic Landing
Name (Assembled Stair:Stair:...) | In
621048 Landing 1 | Ground FFL
621048 Landing 2 | Ground FFL
622611 Landing 1 | Hardstand
622611 Landing 2 | Hardstand
622611 Landing 3 | Hardstand
767068 Landing 1 | Hardstand
767068 Landing 2 | Hardstand
767068 Landing 3 | Hardstand

# IfcSlab: Assembled Stair:190mm max riser 250mm going:141734 (3)
In: Ground FFL
PredefinedType: LANDING
Pset_SlabCommon - IsExternal: no; PitchAngle: 0 deg; Reference: Non-Monolithic Landing
Name (Assembled Stair:Stair:...)
516542 Landing 1
516542 Landing 2
516542 Landing 3

# IfcSlab: Basic Roof:50 (12)
PredefinedType: ROOF; Material: Aluminum 50 mm
Pset_SlabCommon - IsExternal: yes; Reference: 50; ThermalTransmittance: 4600 kg/K/s3
Name (Basic Roof:50:...) | In | PitchAngle (deg)
2 x 362139 | Ground FFL | 30
362223 | Ground FFL | 5
2 x 362305 | Ground FFL | 10
2 x 362950 | Ground FFL | 5
363126 | Ground FFL | 5
363387 | Ground FFL | 5
467344 | Ground FFL | 5 | Group: Model Group:Group 6:617275
712845 | Ground FFL | 5
784254 | First floor | 5

# IfcSlab: Basic Roof:Isopanel 100 (2)
PredefinedType: ROOF; Material: Isopenal 100 mm
Pset_SlabCommon - IsExternal: yes; Reference: Isopanel 100
Name (Basic Roof:Isopanel 100:...) | In | PitchAngle (deg)
363962 | Ground FFL | 3
515924 | Hardstand | 5

# IfcSlab: Floor:Counter (19)
PredefinedType: FLOOR; Material: Wood - Stained 50 mm
Pset_SlabCommon - LoadBearing: no; IsExternal: no; Reference: Counter
Name (Floor:Counter:...) | In
424896 | Ground FFL
424896:2 | Ground FFL
424896:3 | Ground FFL
424896:4 | Ground FFL
424896:5 | Ground FFL
424896:6 | Ground FFL
424896:7 | Ground FFL
424896:8 | Ground FFL
424896:9 | Ground FFL
424896:10 | Ground FFL
424896:11 | Ground FFL
424896:12 | Ground FFL
424896:13 | Ground FFL
424896:14 | Ground FFL
424896:15 | Ground FFL
513588 | 2nd floor | Pset_SlabCommon - PitchAngle: 0 deg
525510 | First floor
525510:2 | First floor
534832 | Hardstand | Pset_SlabCommon - PitchAngle: 0 deg; Group: Model Group:Group 6:617275

# IfcSlab: Floor:Earth, Floor:Earth:362956
In: Ground FFL
PredefinedType: FLOOR; Material: Earth 1200 mm
Pset_SlabCommon - LoadBearing: no; IsExternal: no; PitchAngle: 0 deg; Reference: Earth; ThermalTransmittance: 0.6975 kg/K/s3

# IfcSlab: Floor:Existing floor, Floor:Existing floor:362646
In: Ground FFL
PredefinedType: FLOOR; Material: existing floor 200 mm
Pset_SlabCommon - LoadBearing: no; IsExternal: no; PitchAngle: 0 deg; Reference: Existing floor

# IfcSlab: Floor:Generic 150mm (5)
PredefinedType: FLOOR; Material: cocn slab 200 mm
Pset_SlabCommon - LoadBearing: no; IsExternal: no; Reference: Generic 150mm
Name (Floor:Generic 150mm:...) | In | PitchAngle (deg)
363177 | Ground FFL | 0
363475 | Ground FFL
363475:2 | Ground FFL
385028 | Ground FFL | 0
536015 | Hardstand | 0 | Group: Model Group:Group 6:617275

# IfcSlab: Floor:Mezz (2)
PredefinedType: FLOOR; Material: cocn slab Mezz 200 mm
Pset_SlabCommon - LoadBearing: no; IsExternal: no; Reference: Mezz
Name (Floor:Mezz:...) | In
408204 | First floor
493806 | 2nd floor | Pset_SlabCommon - PitchAngle: 0 deg

# IfcSlab: Floor:catwalk, Floor:catwalk:648266
In: Ceiling 6000
PredefinedType: FLOOR; Material: Copper 70 mm
Pset_SlabCommon - LoadBearing: no; IsExternal: no; PitchAngle: 0 deg; Reference: catwalk; ThermalTransmittance: 5728.57 kg/K/s3

# IfcSlab: Floor:celing (4)
PredefinedType: FLOOR; Material: Gypsum Wall Board 50 mm
Pset_SlabCommon - LoadBearing: no; IsExternal: no; Reference: celing; ThermalTransmittance: 13 kg/K/s3
Name (Floor:celing:...) | In
362767 | Ceiling 6000
362767:2 | Ceiling 6000
759116 | 2nd floor | Pset_SlabCommon - PitchAngle: 0 deg
760150 | 2nd floor | Pset_SlabCommon - PitchAngle: 0 deg

# IfcSlab: Floor:cladding, Floor:cladding:468458
In: First floor
PredefinedType: FLOOR; Material: Cladding 50 mm
Pset_SlabCommon - LoadBearing: no; IsExternal: no; PitchAngle: 0 deg; Reference: cladding

# IfcSlab: Floor:grass, Floor:grass:405613
In: Hardstand
PredefinedType: FLOOR; Material: Grass 150 mm
Pset_SlabCommon - LoadBearing: no; IsExternal: no; PitchAngle: 0 deg; Reference: grass

# IfcSlab: Floor:isopanel ceiling (3)
PredefinedType: FLOOR; Material: Isopenal 100 mm
Pset_SlabCommon - LoadBearing: no; IsExternal: no; PitchAngle: 0 deg; Reference: isopanel ceiling
Name (Floor:isopanel ceiling:...) | In
564417 | First floor
564686 | 2nd floor
620629 | Ground FFL

# IfcSlab: Floor:isopanel ceiling 50 (3)
In: Ceiling 3500
PredefinedType: FLOOR; Material: Isopenal 50 mm
Pset_SlabCommon - LoadBearing: no; IsExternal: no; Reference: isopanel ceiling 50
Name (Floor:isopanel ceiling 50:...)
432452 | Pset_SlabCommon - PitchAngle: 0 deg
444840
444840:2

# IfcSlab: Floor:paving (4)
PredefinedType: FLOOR; Material: paving 150 mm
Pset_SlabCommon - LoadBearing: no; IsExternal: no; Reference: paving
Name (Floor:paving:...) | In
642605 | Hardstand
642605:2 | Hardstand
642605:3 | Hardstand
712260 | Ground FFL | Pset_SlabCommon - PitchAngle: 0 deg

# IfcSlab: Floor:tar (3)
In: Ground FFL
PredefinedType: FLOOR; Material: tar 150 mm
Pset_SlabCommon - LoadBearing: no; Reference: tar; IsExternal: no
Name (Floor:tar:...) | PitchAngle (deg)
362150 | 0
362261 | 0
605127

# IfcStair: Assembled Stair:170mm max riser 270mm going 1500:768833, Assembled Stair:Stair:634342
In: First floor
Pset_StairCommon - IsExternal: no; Reference: 170mm max riser 270mm going 1500; NumberOfRiser: 17; NumberOfTreads: 15; RiserHeight: 168.065 mm; TreadLength: 270 mm

# IfcStair: Assembled Stair:170mm max riser 270mm going:346207 (7)
Pset_StairCommon - IsExternal: no; Reference: 170mm max riser 270mm going; TreadLength: 270 mm
Name (Assembled Stair:Stair:...) | In | NumberOfRiser | NumberOfTreads | RiserHeight (mm)
371358 | Ground FFL | 9 | 8 | 155.556
588793 | Ground FFL | 9 | 8 | 155.556
621048 | Ground FFL | 23 | 20 | 166.667
622611 | Hardstand | 32 | 28 | 167.5
712789 | Hardstand | 12 | 11 | 166.667
767068 | Hardstand | 32 | 28 | 167.5
770226 | Ceiling 3500 | 19 | 18 | 167.5

# IfcStair: Assembled Stair:190mm max riser 250mm going:141734, Assembled Stair:Stair:516542
In: Ground FFL
Pset_StairCommon - IsExternal: no; Reference: 190mm max riser 250mm going; NumberOfRiser: 41; NumberOfTreads: 37; RiserHeight: 167.247 mm; TreadLength: 280 mm

# IfcStairFlight: Assembled Stair:170mm max riser 270mm going 1500:768833 (2)
In: First floor
RiserHeight: 0.551395 mm; TreadLength: 0.885827 mm
Pset_StairFlightCommon - Reference: 50mm Tread 13mm Riser; NosingLength: 0 mm; NumberOfRiser: 17; NumberOfTreads: 15; RiserHeight: 168.065 mm; TreadLength: 270 mm; TreadLengthAtOffset: 270 mm; WalkingLineOffset: 600 mm; WaistThickness: 1200 mm
Name (Assembled Stair:Stair:...) | NumberOfRiser | NumberOfTreads
634342 Run 1 | 9 | 8
634342 Run 2 | 8 | 7

# IfcStairFlight: Assembled Stair:170mm max riser 270mm going:346207 (15)
TreadLength: 0.885827 mm
Pset_StairFlightCommon - Reference: 50mm Tread 13mm Riser; TreadLength: 270 mm; TreadLengthAtOffset: 270 mm; NosingLength: 0 mm
Name (Assembled Stair:Stair:...) | In | NumberOfRiser | NumberOfTreads | RiserHeight (mm) | Pset_StairFlightCommon, NumberOfRiser | Pset_StairFlightCommon, NumberOfTreads | Pset_StairFlightCommon, RiserHeight (mm) | WalkingLineOffset (mm) | WaistThickness (mm)
371358 Run 1 | Ground FFL | 9 | 8 | 0.510353 | 9 | 8 | 155.556 | 750 | 1500
588793 Run 1 | Ground FFL | 9 | 8 | 0.510353 | 9 | 8 | 155.556 | 750 | 1500
621048 Run 1 | Ground FFL | 9 | 8 | 0.546807 | 23 | 20 | 166.667 | 500 | 1000
621048 Run 2 | Ground FFL | 9 | 8 | 0.546807 | 23 | 20 | 166.667 | 500 | 1000
621048 Run 3 | Ground FFL | 5 | 4 | 0.546807 | 23 | 20 | 166.667 | 500 | 1000
622611 Run 1 | Hardstand | 9 | 8 | 0.549541 | 32 | 28 | 167.5 | 600 | 1200
622611 Run 2 | Hardstand | 9 | 8 | 0.549541 | 32 | 28 | 167.5 | 600 | 1200
622611 Run 3 | Hardstand | 9 | 8 | 0.549541 | 32 | 28 | 167.5 | 600 | 1200
622611 Run 4 | Hardstand | 5 | 4 | 0.549541 | 32 | 28 | 167.5 | 600 | 1200
712789 Run 1 | Hardstand | 12 | 11 | 0.546807 | 12 | 11 | 166.667 | 600 | 1200
767068 Run 1 | Hardstand | 9 | 8 | 0.549541 | 32 | 28 | 167.5 | 600 | 1200
767068 Run 2 | Hardstand | 9 | 8 | 0.549541 | 32 | 28 | 167.5 | 600 | 1200
767068 Run 3 | Hardstand | 9 | 8 | 0.549541 | 32 | 28 | 167.5 | 600 | 1200
767068 Run 4 | Hardstand | 5 | 4 | 0.549541 | 32 | 28 | 167.5 | 600 | 1200
770226 Run 1 | Ceiling 3500 | 19 | 18 | 0.549541 | 19 | 18 | 167.5 | 600 | 1200

# IfcStairFlight: Assembled Stair:190mm max riser 250mm going:141734 (4)
In: Ground FFL
RiserHeight: 0.548709 mm; TreadLength: 0.918635 mm
Pset_StairFlightCommon - Reference: 50mm Tread 13mm Riser; NosingLength: 0 mm; NumberOfRiser: 41; NumberOfTreads: 37; RiserHeight: 167.247 mm; TreadLength: 280 mm; TreadLengthAtOffset: 280 mm; WalkingLineOffset: 600 mm; WaistThickness: 1200 mm
Name (Assembled Stair:Stair:...) | NumberOfRiser | NumberOfTreads
516542 Run 1 | 10 | 9
516542 Run 2 | 10 | 9
516542 Run 3 | 10 | 9
516542 Run 4 | 11 | 10

# IfcWall: Basic Wall:Cladding 3, Basic Wall:Cladding 3:362761
In: Ground FFL
Material: Cladding(2)
Pset_WallCommon - LoadBearing: no; ExtendToStructure: no; IsExternal: yes; Reference: Cladding 3

# IfcWall: Basic Wall:Orange (2)
Material: Aluminum, Anodized Silver
Pset_WallCommon - LoadBearing: no; ExtendToStructure: no; IsExternal: yes; Reference: Orange; ThermalTransmittance: 6052.63 kg/K/s3
Name (Basic Wall:Orange:...) | In
640652 | First floor
686998 | Ground FFL

# IfcWall: Basic Wall:Orange wide (4)
In: Ground FFL
Material: Orange
Pset_WallCommon - LoadBearing: no; ExtendToStructure: no; IsExternal: yes; Reference: Orange wide
Name (Basic Wall:Orange wide:...)
362069
362096
362555
362582

# IfcWall: Basic Wall:Translucent sheeting, Basic Wall:Translucent sheeting:444408
In: Ground FFL
Material: Translucent
Pset_WallCommon - LoadBearing: no; ExtendToStructure: no; IsExternal: yes; Reference: Translucent sheeting; ThermalTransmittance: 28.9474 kg/K/s3

# IfcWallStandardCase: Basic Wall:22 Partition (32)
Type - PredefinedType: STANDARD; Material: Partition 22 mm
Pset_WallCommon - LoadBearing: no; ExtendToStructure: no; IsExternal: yes; Reference: 22 Partition
Name (Basic Wall:22 Partition:...) | In
510909 | 2nd floor
511000 | 2nd floor
511001 | 2nd floor
511002 | 2nd floor
511003 | 2nd floor
511006 | 2nd floor
511008 | 2nd floor
525126 | First floor
525157 | First floor
525243 | First floor
527716 | First floor
527762 | First floor
527811 | First floor
527863 | First floor
527902 | First floor
528207 | First floor
528236 | First floor
528270 | First floor
528309 | First floor
528353 | First floor
528413 | First floor
528448 | First floor
528518 | First floor
528558 | First floor
528610 | First floor
533850 | Hardstand | Group: Model Group:Group 6:617275
533852 | Hardstand | Group: Model Group:Group 6:617275
533855 | Hardstand | Group: Model Group:Group 6:617275
535727 | Hardstand | Group: Model Group:Group 6:617275
579930 | First floor
579931 | First floor
579932 | First floor

# IfcWallStandardCase: Basic Wall:300 bund wall (40)
Type - PredefinedType: STANDARD; Material: conc bund 300 mm
Pset_WallCommon - LoadBearing: no; ExtendToStructure: no; IsExternal: yes; Reference: 300 bund wall
Name (Basic Wall:300 bund wall:...) | In
362762 | Ground FFL
362764 | Ground FFL
362765 | Ground FFL
363285 | Ground FFL
363298 | Ground FFL
427756 | Ground FFL
427924 | Ground FFL
428938 | Ground FFL
428953 | Ground FFL
428995 | Ground FFL
429010 | Ground FFL
429025 | Ground FFL
429040 | Ground FFL
429096 | Ground FFL
429111 | Ground FFL
429126 | Ground FFL
429141 | Ground FFL
429156 | Ground FFL
429171 | Ground FFL
429186 | Ground FFL
429201 | Ground FFL
429244 | Ground FFL
429259 | Ground FFL
429274 | Ground FFL
429289 | Ground FFL
429304 | Ground FFL
429319 | Ground FFL
429334 | Ground FFL
429349 | Ground FFL
429389 | Ground FFL
429404 | Ground FFL
429419 | Ground FFL
429434 | Ground FFL
429449 | Ground FFL
429464 | Ground FFL
446745 | Ground FFL
487882 | Ground FFL
579325 | Ground FFL
653766 | Hardstand
653822 | Hardstand

# IfcWallStandardCase: Basic Wall:Cladding, Basic Wall:Cladding:362759
In: Ground FFL
Type - PredefinedType: STANDARD; Material: Cladding 38 mm
Pset_WallCommon - LoadBearing: no; ExtendToStructure: no; IsExternal: yes; Reference: Cladding

# IfcWallStandardCase: Basic Wall:Cladding 2 (3)
In: Ground FFL
Type - PredefinedType: STANDARD; Material: Isopenal 38 mm
Pset_WallCommon - LoadBearing: no; ExtendToStructure: no; IsExternal: yes; Reference: Cladding 2
Name (Basic Wall:Cladding 2:...)
362218
362219
362220

# IfcWallStandardCase: Basic Wall:Cladding 3 (10)
Material: Cladding(2) 38 mm
Pset_WallCommon - LoadBearing: no; ExtendToStructure: no; IsExternal: yes; Reference: Cladding 3
Name (Basic Wall:Cladding 3:...) | In
363284 | Ground FFL
363299 | Ceiling 6000
379943 | Hardstand
379992 | Hardstand
446828 | Ground FFL
453704 | Ground FFL
466679 | Ceiling 6000
468366 | Ground FFL
565829 | Hardstand
624606 | First floor

# IfcWallStandardCase: Basic Wall:Cladding dark (8)
In: Ground FFL
Type - PredefinedType: STANDARD; Material: Side cladding 38 mm
Pset_WallCommon - Reference: Cladding dark; LoadBearing: no; ExtendToStructure: no; IsExternal: yes
Name (Basic Wall:Cladding dark:...)
361914
361915
361917
361918
361939
362010
363984
577523

# IfcWallStandardCase: Basic Wall:Isopanel (72)
Type - PredefinedType: STANDARD; Material: Isopenal 100 mm
Pset_WallCommon - LoadBearing: no; ExtendToStructure: no; IsExternal: yes; Reference: Isopanel
Name (Basic Wall:Isopanel:...) | In
362760 | Ground FFL
362802 | Ground FFL
362803 | Ground FFL
362804 | Ground FFL
362805 | Ground FFL
362807 | Ground FFL
362984 | Ground FFL
363162 | Ground FFL
363169 | Ground FFL
363174 | Ground FFL
364082 | First floor
364083 | First floor
364098 | First floor
387995 | First floor
412638 | Ground FFL
412639 | Ground FFL
412868 | Ground FFL
412869 | Ground FFL
412896 | Ground FFL
412897 | Ground FFL
412901 | Ground FFL
412902 | Ground FFL
412906 | Ground FFL
412907 | Ground FFL
412911 | Ground FFL
412912 | Ground FFL
412916 | Ground FFL
412917 | Ground FFL
412921 | Ground FFL
412922 | Ground FFL
412926 | Ground FFL
412927 | Ground FFL
412931 | Ground FFL
412932 | Ground FFL
412936 | Ground FFL
412937 | Ground FFL
412941 | Ground FFL
412942 | Ground FFL
412946 | Ground FFL
412947 | Ground FFL
412951 | Ground FFL
412952 | Ground FFL
432357 | Ground FFL
448357 | Ground FFL
450361 | First floor
450548 | First floor
452914 | Ground FFL
453520 | Ground FFL
453552 | Ground FFL
454252 | Ground FFL
521149 | 2nd floor
522462 | First floor
525850 | Ground FFL
525979 | Ground FFL
526035 | Ground FFL
526079 | Ground FFL
526143 | Ground FFL
526549 | Ground FFL
526585 | Ground FFL
526646 | Ground FFL
526788 | Ground FFL
526900 | Ground FFL
526981 | Ground FFL
527029 | Ground FFL
549097 | Ground FFL
564587 | Ground FFL
566944 | Ground FFL
586391 | Ground FFL
610970 | Ground FFL
619028 | Ground FFL
650207 | First floor
659460 | Ground FFL

# IfcWallStandardCase: Basic Wall:Isopanel 50mm (3)
In: Ground FFL
Type - PredefinedType: STANDARD; Material: Isopenal 50 mm
Pset_WallCommon - LoadBearing: no; ExtendToStructure: no; IsExternal: yes; Reference: Isopanel 50mm
Name (Basic Wall:Isopanel 50mm:...)
440295
440494
619189

# IfcWallStandardCase: Basic Wall:fence (6)
In: Hardstand
Type - PredefinedType: STANDARD; Material: fence 10 mm
Pset_WallCommon - LoadBearing: no; ExtendToStructure: no; IsExternal: yes; Reference: fence
Name (Basic Wall:fence:...)
464338
464493
464531
464773
464809
673815

# IfcWallStandardCase: Basic Wall:wall 50 Partition, Basic Wall:wall 50 Partition:572816
In: 2nd floor
Type - PredefinedType: STANDARD; Material: Partition 30 mm
Pset_WallCommon - LoadBearing: no; ExtendToStructure: no; IsExternal: yes; Reference: wall 50 Partition

# IfcWallStandardCase: Basic Wall:wall 90 Partition (44)
Type - PredefinedType: STANDARD; Material: Partition 100 mm
Pset_WallCommon - LoadBearing: no; ExtendToStructure: no; IsExternal: yes; Reference: wall 90 Partition
Name (Basic Wall:wall 90 Partition:...) | In
364018 | First floor
364095 | First floor
364096 | First floor
364099 | First floor
364100 | First floor
364299 | First floor
406397 | First floor
406550 | First floor
494750 | 2nd floor
495691 | 2nd floor
495800 | 2nd floor
495859 | 2nd floor
496543 | 2nd floor
496602 | 2nd floor
510385 | 2nd floor
511838 | 2nd floor
511881 | 2nd floor
512010 | 2nd floor
512053 | 2nd floor
522908 | First floor
522992 | First floor
523076 | First floor
523119 | First floor
523165 | First floor
523237 | First floor
523394 | First floor
523439 | First floor
523495 | First floor
523537 | First floor
523611 | First floor
523690 | First floor
524005 | First floor
524080 | First floor
524405 | First floor
524448 | First floor
524473 | First floor
524474 | First floor
524493 | First floor
524562 | First floor
524750 | First floor
525467 | First floor
530615 | First floor
572494 | 2nd floor
621225 | First floor

# IfcWallStandardCase: Basic Wall:wall Brick 230 (5)
Type - PredefinedType: STANDARD; Material: Brick, Common 230 mm
Pset_WallCommon - LoadBearing: no; ExtendToStructure: no; IsExternal: yes; Reference: wall Brick 230; ThermalTransmittance: 2.34783 kg/K/s3
Name (Basic Wall:wall Brick 230:...) | In
532982 | Hardstand | Group: Model Group:Group 6:617275
588425 | Ground FFL
588460 | Ground FFL
588508 | Ground FFL
617776 | Ground FFL | Group: Model Group:Group 6:617275

# IfcWallStandardCase: Basic Wall:wall Brick 270 (11)
Type - PredefinedType: STANDARD; Material: Brick, Common 110 mm, Air 50 mm, Brick, Common 110 mm
Pset_WallCommon - LoadBearing: no; ExtendToStructure: no; IsExternal: yes; Reference: wall Brick 270; ThermalTransmittance: 0.415385 kg/K/s3
Name (Basic Wall:wall Brick 270:...) | In
362133 | Ground FFL
362134 | Ground FFL
362135 | Ground FFL
362136 | Ground FFL
362299 | Ground FFL
362300 | Ground FFL
362301 | Ground FFL
362302 | Ground FFL
532665 | Hardstand | Group: Model Group:Group 6:617275
532735 | Hardstand | Group: Model Group:Group 6:617275
532777 | Hardstand | Group: Model Group:Group 6:617275

# IfcWindow: 0610 x 0610mm, M_Fixed:0610 x 0610mm:536363
In: Hardstand
Type - ParameterTakesPrecedence: no; Sizeable: no; Material: Glass, Sash
OverallHeight: 610 mm; OverallWidth: 610 mm; Group: Model Group:Group 6:617275
Pset_WindowCommon - IsExternal: yes; Reference: 0610 x 0610mm; ThermalTransmittance: 3.6886 kg/K/s3

# IfcWindow: 850 x 900mm (3)
In: Hardstand
Type - ParameterTakesPrecedence: no; Sizeable: no; Classification: B2020100 Windows (Uniformat); Material: Wood - Stained, Glass
OverallHeight: 900 mm; OverallWidth: 850 mm; Group: Model Group:Group 6:617275
Pset_WindowCommon - IsExternal: yes; Reference: 850 x 900mm; FireRating: 0.5h
Name (M_Window-Casement-Double:850 x 900mm:...)
534041
536288
536323
